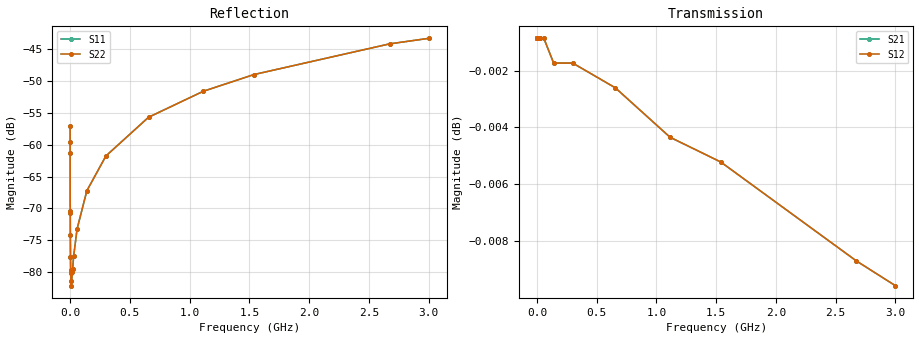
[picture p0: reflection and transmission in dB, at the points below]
! S-Parameter Data Generated by TDK Corporation
! Copyright(C) 2022 TDK Corporation.
! All Rights Reserved.
! TDK P/N: CLLC1AX6S0G475M050AC (Multilayer Ceramic Chip Capacitor)
! Property: C=4.7uF
! Size(LxWxT): 1.6x0.8x0.5mm
! Model Type: s2p (Touchstone File Format Version 1.0)
! Frequency: DC=Yes Start=0.3MHz Stop=3000MHz 402points Log-sweep
! Model Generated on Apr. 15, 2022
! Port Assignments:
!  1 ---| |--- 2
! Applicable Conditions:
!  Temperature = 25 degC
!  DC Bias Voltage = 0 V
!  Small Signal Operation
! Terms and conditions regarding TDK Simulation Models
! (1)This simulation model is being provided solely for informational purposes. Please refer to the specifications of the products in terms of detailed characteristics of such products.
! (2)In no event shall TDK Corporation of any of its subsidiaries be liable for any loss or damage arising, directly or indirectly,
!  From any information contained in this simulation model, including, but not limited to loss or damages arising from any inaccuracies, omissions or errors in connection with such information.
! (3)Any and all copyrights on this simulation model are owned by TDK Corporation.
!  Duplication or redistribution of this simulation model without prior written permission from TDK Corporation is prohibited.
! (4)This simulation model is subject to any modification or change without any prior notice.
! (5)Neither TDK Corporation nor any of its subsidiaries shall make any warranty, express or implied,
!  Including but not limited to the correctness, implied warranties of merchantability and fitness for a particular purpose with respect to this simulation models.
! (6)The use of this simulation model shall be deemed to have consented to the terms and conditions hereof.
# Hz S MA R 50
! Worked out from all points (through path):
!   401 points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, 300 kHz to 3 GHz, reference 50 ohm
!   highest |S21| = 0.00 dB at 2.224 MHz (marker M1); lowest = 0.0 dB at 3 GHz (marker M2)
!   lowest |S11| = -82.1 dB at 9.06 MHz (marker M3), VSWR 1.00, Z = 50 - j0.00076 ohm
!   |S11| at or under -10 dB: start of sweep to end of sweep
!   |S22| runs from -82.1 to -43.3 dB; largest |S21 - S12| = 0
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300000  0.001407 -86.0  0.9999 0.1  0.9999 0.1  0.001407 -86.0
404689  0.001048 -85.3  0.9999 0.1  0.9999 0.1  0.001048 -85.3
486543  0.0008628 -84.3  0.9999 0.0  0.9999 0.0  0.0008628 -84.3
1403210  0.0003031 -75.6  0.9999 0.0  0.9999 0.0  0.0003031 -75.6
1503560  0.0002888 -74.4  0.9999 0.0  0.9999 0.0  0.0002888 -74.4
2223930  0.0001946 -68.5  0.9999 0.0  0.9999 0.0  0.0001946 -68.5
3444460  0.0001306 -55.0  0.9999 0.0  0.9999 0.0  0.0001306 -55.0
4646450  0.0001032 -43.0  0.9999 0.0  0.9999 0.0  0.0001032 -43.0
5094730  9.785e-05 -38.8  0.9999 0.0  0.9999 0.0  9.785e-05 -38.8
6563280  8.478e-05 -25.4  0.9999 0.0  0.9999 0.0  8.478e-05 -25.4
9059860  7.827e-05 -5.6  0.9999 0.0  0.9999 0.0  7.827e-05 -5.6
1.89287e7  9.95e-05 31.4  0.9999 -0.0  0.9999 -0.0  9.95e-05 31.4
2.12384e7  0.0001061 35.2  0.9999 -0.0  0.9999 -0.0  0.0001061 35.2
3e7  0.0001338 45.5  0.9999 -0.0  0.9999 -0.0  0.0001338 45.5
5.84953e7  0.0002182 58.5  0.9999 -0.0  0.9999 -0.0  0.0002182 58.5
1.40321e8  0.0004357 68.7  0.9998 -0.0  0.9998 -0.0  0.0004357 68.7
3e8  0.0008173 74.3  0.9998 -0.0  0.9998 -0.0  0.0008173 74.3
6.56328e8  0.001645 78.1  0.9997 -0.1  0.9997 -0.1  0.001645 78.1
1.11461e9  0.002631 79.8  0.9995 -0.1  0.9995 -0.1  0.002631 79.8
1.53858e9  0.00356 80.7  0.9994 -0.2  0.9994 -0.2  0.00356 80.7
2.67375e9  0.0062 80.6  0.999 -0.4  0.999 -0.4  0.0062 80.6
3e9  0.006849 80.6  0.9989 -0.4  0.9989 -0.4  0.006849 80.6
